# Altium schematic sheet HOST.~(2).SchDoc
size A3; SheetNumber: 4; SheetTotal: 4

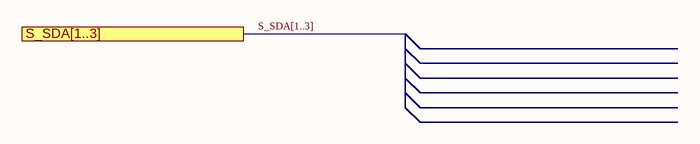
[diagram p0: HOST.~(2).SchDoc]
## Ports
S_SDA[1..3]

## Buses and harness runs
bus S_SDA[1..3] = port S_SDA[1..3]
